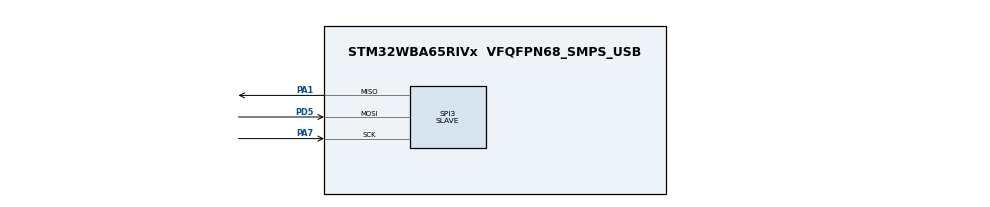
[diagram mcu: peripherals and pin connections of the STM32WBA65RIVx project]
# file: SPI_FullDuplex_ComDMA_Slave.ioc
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CORTEX_M33_NS.userName=CORTEX_M33
GPDMA1.LINKALLOCATEDPORT_GPDMACH6=DMA_LINK_ALLOCATED_PORT1
GPDMA1.LINKALLOCATEDPORT_GPDMACH7=DMA_LINK_ALLOCATED_PORT1
GPDMA1.PRIORITY_LL_GPDMACH6=DMA_LOW_PRIORITY_HIGH_WEIGHT
GPDMA1.PRIORITY_LL_GPDMACH7=DMA_LOW_PRIORITY_HIGH_WEIGHT
Linkedlist.MDMA_Channel0.GP_SW.0.BlkHWRequest=DMA_BREQ_SINGLE_BURST
Linkedlist.MDMA_Channel0.GP_SW.0.DATAEXCHANGEDESRCBYTE=NONE
Linkedlist.MDMA_Channel0.GP_SW.0.DATAEXCHANGEDESTBYTE=NONE
Linkedlist.MDMA_Channel0.GP_SW.0.DATAEXCHANGEDESTHALFWORD=NONE
Linkedlist.MDMA_Channel0.GP_SW.0.DataAlignment=DMA_DATA_RIGHTALIGN_ZEROPADDED
Linkedlist.MDMA_Channel0.GP_SW.0.DataHandling=ENABLE
Linkedlist.MDMA_Channel0.GP_SW.0.DataSize=0
Linkedlist.MDMA_Channel0.GP_SW.0.DestBurstLength=1
Linkedlist.MDMA_Channel0.GP_SW.0.DestDataWidth=DMA_DEST_DATAWIDTH_BYTE
Linkedlist.MDMA_Channel0.GP_SW.0.DestInc=DMA_DINC_FIXED
Linkedlist.MDMA_Channel0.GP_SW.0.Direction=DMA_MEMORY_TO_PERIPH
Linkedlist.MDMA_Channel0.GP_SW.0.DstAddress=0
Linkedlist.MDMA_Channel0.GP_SW.0.Instance=MDMA_Channel0
Linkedlist.MDMA_Channel0.GP_SW.0.LL_MASTERDMA=GPDMA1
Linkedlist.MDMA_Channel0.GP_SW.0.LL_NAME=Queue_tx
Linkedlist.MDMA_Channel0.GP_SW.0.LL_TYPE=LINEAR
Linkedlist.MDMA_Channel0.GP_SW.0.NODE_NAME=Node_tx
Linkedlist.MDMA_Channel0.GP_SW.0.Requestforcodegen=GPDMA1_REQUEST_SPI3_TX
Linkedlist.MDMA_Channel0.GP_SW.0.SrcAddress=0
Linkedlist.MDMA_Channel0.GP_SW.0.SrcBurstLength=1
Linkedlist.MDMA_Channel0.GP_SW.0.SrcDataWidth=DMA_SRC_DATAWIDTH_BYTE
Linkedlist.MDMA_Channel0.GP_SW.0.SrcInc=DMA_SINC_INCREMENTED
Linkedlist.MDMA_Channel0.GP_SW.0.TransferAllocatedPortSrc=DMA_SRC_ALLOCATED_PORT1
Linkedlist.MDMA_Channel0.GP_SW.0.TransferEventMode=DMA_TCEM_BLOCK_TRANSFER
Linkedlist.MDMA_Channel0.GP_SW.0.TriggerPolarity=DMA_TRIG_POLARITY_MASKED
Linkedlist.MDMA_Channel0.Request0=GP_SW
Linkedlist.MDMA_Channel0.RequestsNb=1
Linkedlist.MDMA_Channel1.GP_SW.0.BlkHWRequest=DMA_BREQ_SINGLE_BURST
Linkedlist.MDMA_Channel1.GP_SW.0.DATAEXCHANGEDESRCBYTE=NONE
Linkedlist.MDMA_Channel1.GP_SW.0.DATAEXCHANGEDESTBYTE=NONE
Linkedlist.MDMA_Channel1.GP_SW.0.DATAEXCHANGEDESTHALFWORD=NONE
Linkedlist.MDMA_Channel1.GP_SW.0.DataAlignment=DMA_DATA_RIGHTALIGN_ZEROPADDED
Linkedlist.MDMA_Channel1.GP_SW.0.DataHandling=ENABLE
Linkedlist.MDMA_Channel1.GP_SW.0.DataSize=0
Linkedlist.MDMA_Channel1.GP_SW.0.DestBurstLength=1
Linkedlist.MDMA_Channel1.GP_SW.0.DestDataWidth=DMA_DEST_DATAWIDTH_BYTE
Linkedlist.MDMA_Channel1.GP_SW.0.DestInc=DMA_DINC_INCREMENTED
Linkedlist.MDMA_Channel1.GP_SW.0.Direction=DMA_PERIPH_TO_MEMORY
Linkedlist.MDMA_Channel1.GP_SW.0.DstAddress=0
Linkedlist.MDMA_Channel1.GP_SW.0.Instance=MDMA_Channel1
Linkedlist.MDMA_Channel1.GP_SW.0.LL_MASTERDMA=GPDMA1
Linkedlist.MDMA_Channel1.GP_SW.0.LL_NAME=Queue_rx
Linkedlist.MDMA_Channel1.GP_SW.0.LL_TYPE=LINEAR
Linkedlist.MDMA_Channel1.GP_SW.0.NODE_NAME=Node_rx
Linkedlist.MDMA_Channel1.GP_SW.0.Requestforcodegen=GPDMA1_REQUEST_SPI3_RX
Linkedlist.MDMA_Channel1.GP_SW.0.SrcAddress=0
Linkedlist.MDMA_Channel1.GP_SW.0.SrcBurstLength=1
Linkedlist.MDMA_Channel1.GP_SW.0.SrcDataWidth=DMA_SRC_DATAWIDTH_BYTE
Linkedlist.MDMA_Channel1.GP_SW.0.SrcInc=DMA_SINC_FIXED
Linkedlist.MDMA_Channel1.GP_SW.0.TransferAllocatedPortSrc=DMA_SRC_ALLOCATED_PORT0
Linkedlist.MDMA_Channel1.GP_SW.0.TransferEventMode=DMA_TCEM_BLOCK_TRANSFER
Linkedlist.MDMA_Channel1.GP_SW.0.TriggerPolarity=DMA_TRIG_POLARITY_MASKED
Linkedlist.MDMA_Channel1.Request0=GP_SW
Linkedlist.MDMA_Channel1.RequestsNb=1
Linkedlist.RequestSet0=MDMA_Channel0
Linkedlist.RequestSet1=MDMA_Channel1
Linkedlist.RequestSetsNb=2
Mcu.Family=STM32WBA
Mcu.Name=STM32WBA65RIVx
Mcu.Package=VFQFPN68_SMPS_USB
NVIC.GPDMA1_Channel6_IRQn=true\:0\:0\:false\:false\:true\:true\:true\:true
NVIC.GPDMA1_Channel7_IRQn=true\:0\:0\:false\:false\:true\:true\:true\:true
NVIC.PriorityGroup=NVIC_PRIORITYGROUP_4
NVIC.SPI3_IRQn=true\:0\:0\:false\:false\:true\:true\:true\:true
OSC_IN.Mode=HSE-External-Oscillator
OSC_IN.PinAttribute=CortexM33
OSC_IN.Signal=RCC_OSC_IN
OSC_OUT.Mode=HSE-External-Oscillator
OSC_OUT.PinAttribute=CortexM33
OSC_OUT.Signal=RCC_OSC_OUT
PA1.GPIO_Speed=GPIO_SPEED_FREQ_HIGH
PA1.Mode=Full_Duplex_Slave
PA1.PinAttribute=CortexM33
PA1.Signal=SPI3_MISO
PA7.GPIO_Speed=GPIO_SPEED_FREQ_HIGH
PA7.Mode=Full_Duplex_Slave
PA7.PinAttribute=CortexM33
PA7.Signal=SPI3_SCK
PD5.GPIO_Speed=GPIO_SPEED_FREQ_HIGH
PD5.Mode=Full_Duplex_Slave
PD5.PinAttribute=CortexM33
PD5.Signal=SPI3_MOSI
ProjectManager.HeapSize=0x200
ProjectManager.StackSize=0x400
ProjectManager.TargetToolchain=EWARM V9.20
RCC.ADCFreq_Value=100000000
RCC.AHB5CLKDivider=DIV4
RCC.AHBFreq_Value=100000000
RCC.APB1Freq_Value=100000000
RCC.APB1TimFreq_Value=100000000
RCC.APB2Freq_Value=100000000
RCC.APB2TimFreq_Value=100000000
RCC.CortexFreq_Value=12500000
RCC.HCLKFreq_Value=100000000
RCC.HSE_VALUE=32000000
RCC.HSI_VALUE=16000000
RCC.LSE_VALUE=32768
RCC.LSI1_VALUE=32000
RCC.LSI2_VALUE=32000
RCC.PLLFRACN=4096
RCC.PLLM=2
RCC.PLLN=12
RCC.PLLSourceVirtual=RCC_PLLSOURCE_HSE
RCC.SYSCLKFreq_VALUE=100000000
RCC.SYSCLKSourceVirtual=RCC_SYSCLKSOURCE_PLLCLK
RCC.VCOOutputFreq_Value=200000000
SPI3.Direction=SPI_DIRECTION_2LINES
SPI3.Mode=SPI_MODE_SLAVE
SPI3.VirtualType=VM_SLAVE
VP_CORTEX_M33_NS_VS_Hclk.Mode=Hclk_Mode
VP_GPDMA1_VS_GPDMACH6.Mode=LINKEDLIST_GPDMACH6
VP_GPDMA1_VS_GPDMACH7.Mode=LINKEDLIST_GPDMACH7
VP_ICACHE_VS_ICACHE.Mode=DirectMappedCache
VP_PWR_VS_SECSignals.Mode=Security/Privilege
board=custom

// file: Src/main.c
/* USER CODE BEGIN Header */
/**
  ******************************************************************************
  * @file           : main.c
  * @brief          : Main program body
  ******************************************************************************
  * @attention
  *
  * Copyright (c) 2024 STMicroelectronics.
  * All rights reserved.
  *
  * This software is licensed under terms that can be found in the LICENSE file
  * in the root directory of this software component.
  * If no LICENSE file comes with this software, it is provided AS-IS.
  *
  ******************************************************************************
  */
/* USER CODE END Header */
#include "main.h"

/* USER CODE BEGIN PTD */
enum {
	TRANSFER_WAIT,
	TRANSFER_COMPLETE,
	TRANSFER_ERROR
};
/* USER CODE END PTD */

/* USER CODE BEGIN PD */
uint8_t aTxBuffer[] = "****SPI - Two Boards communication based on DMA **** SPI Message ******** SPI Message ******** SPI Message ****";

/* Buffer used for reception */
#define BUFFER_ALIGNED_SIZE (((BUFFERSIZE+31)/32)*32)
ALIGN_32BYTES(uint8_t aRxBuffer[BUFFER_ALIGNED_SIZE]);

/* transfer state */
__IO uint32_t wTransferState = TRANSFER_WAIT;
/* USER CODE END PD */

DMA_HandleTypeDef handle_GPDMA1_Channel7;
DMA_HandleTypeDef handle_GPDMA1_Channel6;

SPI_HandleTypeDef hspi3;

void SystemClock_Config(void);
static void MX_GPDMA1_Init(void);
static void MX_GPIO_Init(void);
static void MX_ICACHE_Init(void);
static void MX_SPI3_Init(void);
/* USER CODE BEGIN PFP */
static uint16_t Buffercmp(uint8_t *pBuffer1, uint8_t *pBuffer2, uint16_t BufferLength);
/* USER CODE END PFP */

int main(void)
{

  /* USER CODE BEGIN 1 */
  /* STM32WBAxx HAL library initialization:
       - Systick timer is configured by default as source of time base, but user
             can eventually implement his proper time base source (a general purpose
             timer for example or other time source), keeping in mind that Time base
             duration should be kept 1ms since PPP_TIMEOUT_VALUEs are defined and
             handled in milliseconds basis.
       - Set NVIC Group Priority to 4
       - Low Level Initialization
     */
  /* USER CODE END 1 */

  /* MCU Configuration--------------------------------------------------------*/

  /* Reset of all peripherals, Initializes the Flash interface and the Systick. */
  HAL_Init();

  /* Configure the system clock */
  SystemClock_Config();

  /* USER CODE BEGIN SysInit */
  /* Configure LD1 and LD3 */
  BSP_LED_Init(LD1);
  BSP_LED_Init(LD3);
  /* USER CODE END SysInit */

  /* Initialize all configured peripherals */
  MX_GPDMA1_Init();
  MX_GPIO_Init();
  MX_ICACHE_Init();
  MX_SPI3_Init();
  /* USER CODE BEGIN 2 */

  MX_Queue_tx_Config();
  HAL_DMAEx_List_LinkQ(&handle_GPDMA1_Channel7, &Queue_tx);
  __HAL_LINKDMA(&hspi3, hdmatx, handle_GPDMA1_Channel7);
  MX_Queue_rx_Config();
  HAL_DMAEx_List_LinkQ(&handle_GPDMA1_Channel6, &Queue_rx);
  __HAL_LINKDMA(&hspi3, hdmarx, handle_GPDMA1_Channel6);

  /*##-2- Start the Full Duplex Communication process ########################*/
  /* While the SPI in TransmitReceive process, user can transmit data through
     "aTxBuffer" buffer & receive data through "aRxBuffer" */
  if(HAL_SPI_TransmitReceive_DMA(&hspi3, (uint8_t*)aTxBuffer, (uint8_t *)aRxBuffer, BUFFERSIZE) != HAL_OK)
  {
    /* Transfer error in transmission process */
    Error_Handler();
  }

  /*##-3- Wait for the end of the transfer ###################################*/
  /*  Before starting a new communication transfer, you must wait the callback call
      to get the transfer complete confirmation or an error detection.
      For simplicity reasons, this example is just waiting till the end of the
      transfer, but application may perform other tasks while transfer operation
      is ongoing. */
  while (wTransferState == TRANSFER_WAIT)
  {
  }

  switch(wTransferState)
  {
    case TRANSFER_COMPLETE :
      /*##-4- Compare the sent and received buffers ##############################*/
      if(Buffercmp((uint8_t*)aTxBuffer, (uint8_t*)aRxBuffer, BUFFERSIZE))
      {
        /* Processing Error */
        Error_Handler();
      }
    break;
    default :
      Error_Handler();
    break;
  }
  /* USER CODE END 2 */

  /* Infinite loop */
  while (1)
  {

  }
}

void SystemClock_Config(void)
{
  RCC_OscInitTypeDef RCC_OscInitStruct = {0};
  RCC_ClkInitTypeDef RCC_ClkInitStruct = {0};

  /** Supply configuration update enable
  */
  HAL_PWREx_ConfigSupply(PWR_LDO_SUPPLY);

  /** Configure the main internal regulator output voltage
  */
  if (HAL_PWREx_ControlVoltageScaling(PWR_REGULATOR_VOLTAGE_SCALE1) != HAL_OK)
  {
    Error_Handler();
  }

  /** Initializes the CPU, AHB and APB busses clocks
  */
  RCC_OscInitStruct.OscillatorType = RCC_OSCILLATORTYPE_HSE;
  RCC_OscInitStruct.HSEState = RCC_HSE_ON;
  RCC_OscInitStruct.HSEDiv = RCC_HSE_DIV1;
  RCC_OscInitStruct.PLL1.PLLState = RCC_PLL_ON;
  RCC_OscInitStruct.PLL1.PLLSource = RCC_PLLSOURCE_HSE;
  RCC_OscInitStruct.PLL1.PLLM = 2;
  RCC_OscInitStruct.PLL1.PLLN = 12;
  RCC_OscInitStruct.PLL1.PLLP = 2;
  RCC_OscInitStruct.PLL1.PLLQ = 2;
  RCC_OscInitStruct.PLL1.PLLR = 2;
  RCC_OscInitStruct.PLL1.PLLFractional = 4096;
  if (HAL_RCC_OscConfig(&RCC_OscInitStruct) != HAL_OK)
  {
    Error_Handler();
  }

  /** Initializes the CPU, AHB and APB busses clocks
  */
  RCC_ClkInitStruct.ClockType = RCC_CLOCKTYPE_HCLK|RCC_CLOCKTYPE_SYSCLK
                              |RCC_CLOCKTYPE_PCLK1|RCC_CLOCKTYPE_PCLK2
                              |RCC_CLOCKTYPE_PCLK7|RCC_CLOCKTYPE_HCLK5;
  RCC_ClkInitStruct.SYSCLKSource = RCC_SYSCLKSOURCE_PLLCLK;
  RCC_ClkInitStruct.AHBCLKDivider = RCC_SYSCLK_DIV1;
  RCC_ClkInitStruct.APB1CLKDivider = RCC_HCLK_DIV1;
  RCC_ClkInitStruct.APB2CLKDivider = RCC_HCLK_DIV1;
  RCC_ClkInitStruct.APB7CLKDivider = RCC_HCLK_DIV1;
  RCC_ClkInitStruct.AHB5_PLL1_CLKDivider = RCC_SYSCLK_PLL1_DIV4;
  RCC_ClkInitStruct.AHB5_HSEHSI_CLKDivider = RCC_SYSCLK_HSEHSI_DIV1;

  if (HAL_RCC_ClockConfig(&RCC_ClkInitStruct, FLASH_LATENCY_3) != HAL_OK)
  {
    Error_Handler();
  }
}

static void MX_GPDMA1_Init(void)
{

  /* Peripheral clock enable */
  __HAL_RCC_GPDMA1_CLK_ENABLE();

  /* GPDMA1 interrupt Init */
    HAL_NVIC_SetPriority(GPDMA1_Channel6_IRQn, 0, 0);
    HAL_NVIC_EnableIRQ(GPDMA1_Channel6_IRQn);
    HAL_NVIC_SetPriority(GPDMA1_Channel7_IRQn, 0, 0);
    HAL_NVIC_EnableIRQ(GPDMA1_Channel7_IRQn);

  handle_GPDMA1_Channel7.Instance = GPDMA1_Channel7;
  handle_GPDMA1_Channel7.InitLinkedList.Priority = DMA_LOW_PRIORITY_HIGH_WEIGHT;
  handle_GPDMA1_Channel7.InitLinkedList.LinkStepMode = DMA_LSM_FULL_EXECUTION;
  handle_GPDMA1_Channel7.InitLinkedList.LinkAllocatedPort = DMA_LINK_ALLOCATED_PORT1;
  handle_GPDMA1_Channel7.InitLinkedList.TransferEventMode = DMA_TCEM_LAST_LL_ITEM_TRANSFER;
  handle_GPDMA1_Channel7.InitLinkedList.LinkedListMode = DMA_LINKEDLIST_NORMAL;
  if (HAL_DMAEx_List_Init(&handle_GPDMA1_Channel7) != HAL_OK)
  {
    Error_Handler();
  }
  if (HAL_DMA_ConfigChannelAttributes(&handle_GPDMA1_Channel7, DMA_CHANNEL_NPRIV) != HAL_OK)
  {
    Error_Handler();
  }
  handle_GPDMA1_Channel6.Instance = GPDMA1_Channel6;
  handle_GPDMA1_Channel6.InitLinkedList.Priority = DMA_LOW_PRIORITY_HIGH_WEIGHT;
  handle_GPDMA1_Channel6.InitLinkedList.LinkStepMode = DMA_LSM_FULL_EXECUTION;
  handle_GPDMA1_Channel6.InitLinkedList.LinkAllocatedPort = DMA_LINK_ALLOCATED_PORT1;
  handle_GPDMA1_Channel6.InitLinkedList.TransferEventMode = DMA_TCEM_LAST_LL_ITEM_TRANSFER;
  handle_GPDMA1_Channel6.InitLinkedList.LinkedListMode = DMA_LINKEDLIST_NORMAL;
  if (HAL_DMAEx_List_Init(&handle_GPDMA1_Channel6) != HAL_OK)
  {
    Error_Handler();
  }
  if (HAL_DMA_ConfigChannelAttributes(&handle_GPDMA1_Channel6, DMA_CHANNEL_NPRIV) != HAL_OK)
  {
    Error_Handler();
  }

}

static void MX_ICACHE_Init(void)
{

  /** Enable instruction cache in 1-way (direct mapped cache)
  */
  if (HAL_ICACHE_ConfigAssociativityMode(ICACHE_1WAY) != HAL_OK)
  {
    Error_Handler();
  }
  if (HAL_ICACHE_Enable() != HAL_OK)
  {
    Error_Handler();
  }

}

static void MX_SPI3_Init(void)
{

  /* SPI3 parameter configuration*/
  hspi3.Instance = SPI3;
  hspi3.Init.Mode = SPI_MODE_SLAVE;
  hspi3.Init.Direction = SPI_DIRECTION_2LINES;
  hspi3.Init.DataSize = SPI_DATASIZE_8BIT;
  hspi3.Init.CLKPolarity = SPI_POLARITY_LOW;
  hspi3.Init.CLKPhase = SPI_PHASE_1EDGE;
  hspi3.Init.NSS = SPI_NSS_SOFT;
  hspi3.Init.FirstBit = SPI_FIRSTBIT_MSB;
  hspi3.Init.TIMode = SPI_TIMODE_DISABLE;
  hspi3.Init.CRCCalculation = SPI_CRCCALCULATION_DISABLE;
  hspi3.Init.CRCPolynomial = 0x7;
  hspi3.Init.NSSPMode = SPI_NSS_PULSE_DISABLE;
  hspi3.Init.NSSPolarity = SPI_NSS_POLARITY_LOW;
  hspi3.Init.FifoThreshold = SPI_FIFO_THRESHOLD_01DATA;
  hspi3.Init.MasterSSIdleness = SPI_MASTER_SS_IDLENESS_00CYCLE;
  hspi3.Init.MasterInterDataIdleness = SPI_MASTER_INTERDATA_IDLENESS_00CYCLE;
  hspi3.Init.MasterReceiverAutoSusp = SPI_MASTER_RX_AUTOSUSP_DISABLE;
  hspi3.Init.MasterKeepIOState = SPI_MASTER_KEEP_IO_STATE_DISABLE;
  hspi3.Init.IOSwap = SPI_IO_SWAP_DISABLE;
  hspi3.Init.ReadyMasterManagement = SPI_RDY_MASTER_MANAGEMENT_INTERNALLY;
  hspi3.Init.ReadyPolarity = SPI_RDY_POLARITY_HIGH;
  if (HAL_SPI_Init(&hspi3) != HAL_OK)
  {
    Error_Handler();
  }

}

static void MX_GPIO_Init(void)
{

  /* GPIO Ports Clock Enable */
  __HAL_RCC_GPIOA_CLK_ENABLE();
  __HAL_RCC_GPIOD_CLK_ENABLE();

}

/* USER CODE BEGIN 4 */
/**
  * @brief  TxRx Transfer completed callback.
  * @param  hspi: SPI handle
  * @note   This example shows a simple way to report end of DMA TxRx transfer, and
  *         you can add your own implementation.
  * @retval None
  */
void HAL_SPI_TxRxCpltCallback(SPI_HandleTypeDef *hspi)
{
  /* Turn LD1 on: Transfer in transmission/reception process is complete */
  BSP_LED_On(LD1);
  wTransferState = TRANSFER_COMPLETE;
}

/**
  * @brief  SPI error callbacks.
  * @param  hspi: SPI handle
  * @note   This example shows a simple way to report transfer error, and you can
  *         add your own implementation.
  * @retval None
  */
void HAL_SPI_ErrorCallback(SPI_HandleTypeDef *hspi)
{
  wTransferState = TRANSFER_ERROR;
}

/**
  * @brief  Compares two buffers.
  * @param  pBuffer1, pBuffer2: buffers to be compared.
  * @param  BufferLength: buffer's length
  * @retval 0  : pBuffer1 identical to pBuffer2
  *         >0 : pBuffer1 differs from pBuffer2
  */
static uint16_t Buffercmp(uint8_t *pBuffer1, uint8_t *pBuffer2, uint16_t BufferLength)
{
  while (BufferLength--)
  {
    if((*pBuffer1) != *pBuffer2)
    {
      return BufferLength;
    }
    pBuffer1++;
    pBuffer2++;
  }

  return 0;
}

/* USER CODE END 4 */

void Error_Handler(void)
{
  /* USER CODE BEGIN Error_Handler_Debug */
  /* User can add his own implementation to report the HAL error return state */
  /* Turn LD1 off */
  BSP_LED_Off(LD1);
  /* Toggle LD3 for error */
  while(1)
  {
    BSP_LED_Toggle(LD3);
    HAL_Delay(1000);
  }
  /* USER CODE END Error_Handler_Debug */
}
